VERSION 5.8 ;
BUSBITCHARS "[]" ;
DIVIDERCHAR "/" ;
UNITS
    DATABASE MICRONS 1000 ;
END UNITS

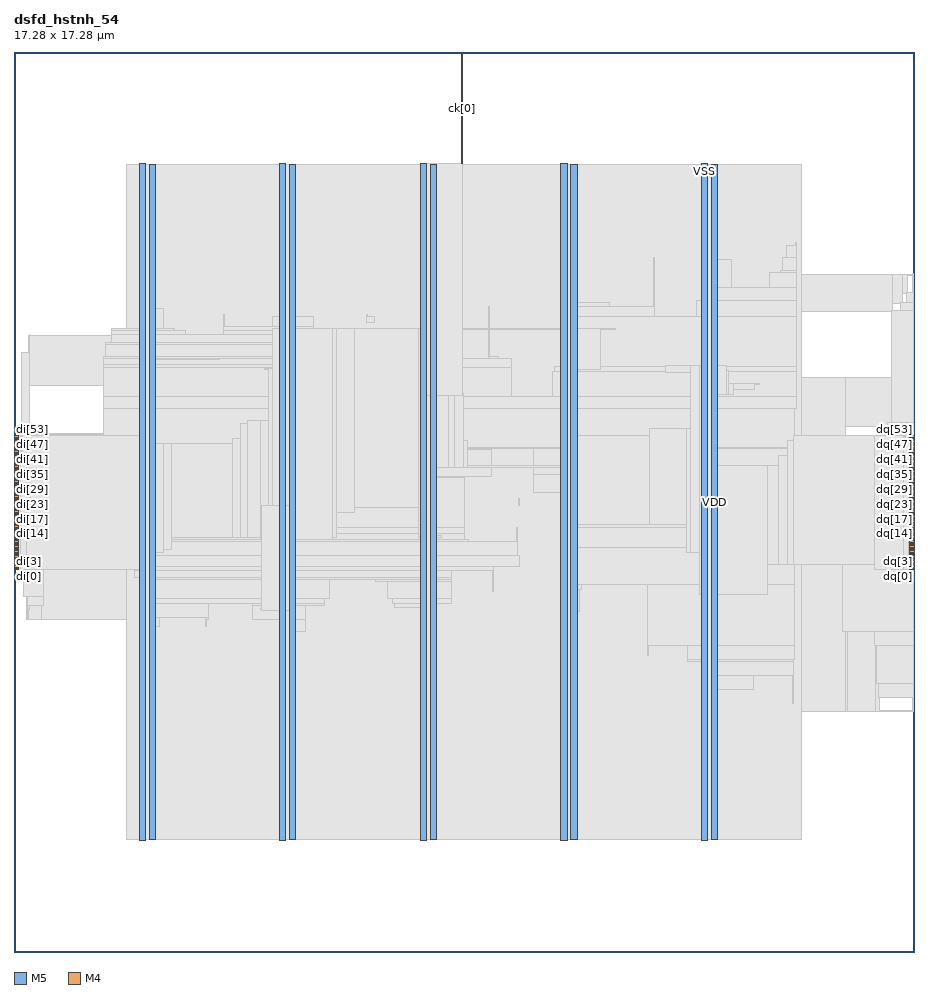
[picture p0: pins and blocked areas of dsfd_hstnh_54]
MACRO dsfd_hstnh_54
  FOREIGN dsfd_hstnh_54 0 0 ;
  CLASS BLOCK ;
  SIZE 17.28 BY 17.28 ;
  PIN ck[0]
    DIRECTION INPUT ;
    USE SIGNAL ;
    PORT
      LAYER M5 ;
        RECT  8.592 17.196 8.616 17.28 ;
    END
    PORT
      LAYER M5 ;
        RECT  8.592 15.143 8.616 17.232 ;
    END
  END ck[0]
  PIN di[0]
    DIRECTION INPUT ;
    USE SIGNAL ;
    PORT
      LAYER M4 ;
        RECT  0 7.344 0.084 7.368 ;
    END
  END di[0]
  PIN di[10]
    DIRECTION INPUT ;
    USE SIGNAL ;
    PORT
      LAYER M4 ;
        RECT  0 7.824 0.084 7.848 ;
    END
  END di[10]
  PIN di[11]
    DIRECTION INPUT ;
    USE SIGNAL ;
    PORT
      LAYER M4 ;
        RECT  0 7.872 0.084 7.896 ;
    END
  END di[11]
  PIN di[12]
    DIRECTION INPUT ;
    USE SIGNAL ;
    PORT
      LAYER M4 ;
        RECT  0 7.92 0.084 7.944 ;
    END
  END di[12]
  PIN di[13]
    DIRECTION INPUT ;
    USE SIGNAL ;
    PORT
      LAYER M4 ;
        RECT  0 7.968 0.084 7.992 ;
    END
  END di[13]
  PIN di[14]
    DIRECTION INPUT ;
    USE SIGNAL ;
    PORT
      LAYER M4 ;
        RECT  0 8.016 0.084 8.04 ;
    END
  END di[14]
  PIN di[15]
    DIRECTION INPUT ;
    USE SIGNAL ;
    PORT
      LAYER M4 ;
        RECT  0 8.064 0.084 8.088 ;
    END
  END di[15]
  PIN di[16]
    DIRECTION INPUT ;
    USE SIGNAL ;
    PORT
      LAYER M4 ;
        RECT  0 8.112 0.084 8.136 ;
    END
  END di[16]
  PIN di[17]
    DIRECTION INPUT ;
    USE SIGNAL ;
    PORT
      LAYER M4 ;
        RECT  0 8.16 0.084 8.184 ;
    END
  END di[17]
  PIN di[18]
    DIRECTION INPUT ;
    USE SIGNAL ;
    PORT
      LAYER M4 ;
        RECT  0 8.208 0.084 8.232 ;
    END
  END di[18]
  PIN di[19]
    DIRECTION INPUT ;
    USE SIGNAL ;
    PORT
      LAYER M4 ;
        RECT  0 8.256 0.084 8.28 ;
    END
  END di[19]
  PIN di[1]
    DIRECTION INPUT ;
    USE SIGNAL ;
    PORT
      LAYER M4 ;
        RECT  0 7.392 0.084 7.416 ;
    END
  END di[1]
  PIN di[20]
    DIRECTION INPUT ;
    USE SIGNAL ;
    PORT
      LAYER M4 ;
        RECT  0 8.304 0.084 8.328 ;
    END
  END di[20]
  PIN di[21]
    DIRECTION INPUT ;
    USE SIGNAL ;
    PORT
      LAYER M4 ;
        RECT  0 8.352 0.084 8.376 ;
    END
  END di[21]
  PIN di[22]
    DIRECTION INPUT ;
    USE SIGNAL ;
    PORT
      LAYER M4 ;
        RECT  0 8.4 0.084 8.424 ;
    END
  END di[22]
  PIN di[23]
    DIRECTION INPUT ;
    USE SIGNAL ;
    PORT
      LAYER M4 ;
        RECT  0 8.448 0.084 8.472 ;
    END
  END di[23]
  PIN di[24]
    DIRECTION INPUT ;
    USE SIGNAL ;
    PORT
      LAYER M4 ;
        RECT  0 8.496 0.084 8.52 ;
    END
  END di[24]
  PIN di[25]
    DIRECTION INPUT ;
    USE SIGNAL ;
    PORT
      LAYER M4 ;
        RECT  0 8.544 0.084 8.568 ;
    END
  END di[25]
  PIN di[26]
    DIRECTION INPUT ;
    USE SIGNAL ;
    PORT
      LAYER M4 ;
        RECT  0 8.592 0.084 8.616 ;
    END
  END di[26]
  PIN di[27]
    DIRECTION INPUT ;
    USE SIGNAL ;
    PORT
      LAYER M4 ;
        RECT  0 8.64 0.084 8.664 ;
    END
  END di[27]
  PIN di[28]
    DIRECTION INPUT ;
    USE SIGNAL ;
    PORT
      LAYER M4 ;
        RECT  0 8.688 0.084 8.712 ;
    END
  END di[28]
  PIN di[29]
    DIRECTION INPUT ;
    USE SIGNAL ;
    PORT
      LAYER M4 ;
        RECT  0 8.736 0.084 8.76 ;
    END
  END di[29]
  PIN di[2]
    DIRECTION INPUT ;
    USE SIGNAL ;
    PORT
      LAYER M4 ;
        RECT  0 7.44 0.084 7.464 ;
    END
  END di[2]
  PIN di[30]
    DIRECTION INPUT ;
    USE SIGNAL ;
    PORT
      LAYER M4 ;
        RECT  0 8.784 0.084 8.808 ;
    END
  END di[30]
  PIN di[31]
    DIRECTION INPUT ;
    USE SIGNAL ;
    PORT
      LAYER M4 ;
        RECT  0 8.832 0.084 8.856 ;
    END
  END di[31]
  PIN di[32]
    DIRECTION INPUT ;
    USE SIGNAL ;
    PORT
      LAYER M4 ;
        RECT  0 8.88 0.084 8.904 ;
    END
  END di[32]
  PIN di[33]
    DIRECTION INPUT ;
    USE SIGNAL ;
    PORT
      LAYER M4 ;
        RECT  0 8.928 0.084 8.952 ;
    END
  END di[33]
  PIN di[34]
    DIRECTION INPUT ;
    USE SIGNAL ;
    PORT
      LAYER M4 ;
        RECT  0 8.976 0.084 9 ;
    END
  END di[34]
  PIN di[35]
    DIRECTION INPUT ;
    USE SIGNAL ;
    PORT
      LAYER M4 ;
        RECT  0 9.024 0.084 9.048 ;
    END
  END di[35]
  PIN di[36]
    DIRECTION INPUT ;
    USE SIGNAL ;
    PORT
      LAYER M4 ;
        RECT  0 9.072 0.084 9.096 ;
    END
  END di[36]
  PIN di[37]
    DIRECTION INPUT ;
    USE SIGNAL ;
    PORT
      LAYER M4 ;
        RECT  0 9.12 0.084 9.144 ;
    END
  END di[37]
  PIN di[38]
    DIRECTION INPUT ;
    USE SIGNAL ;
    PORT
      LAYER M4 ;
        RECT  0 9.168 0.084 9.192 ;
    END
  END di[38]
  PIN di[39]
    DIRECTION INPUT ;
    USE SIGNAL ;
    PORT
      LAYER M4 ;
        RECT  0 9.216 0.084 9.24 ;
    END
  END di[39]
  PIN di[3]
    DIRECTION INPUT ;
    USE SIGNAL ;
    PORT
      LAYER M4 ;
        RECT  0 7.488 0.084 7.512 ;
    END
  END di[3]
  PIN di[40]
    DIRECTION INPUT ;
    USE SIGNAL ;
    PORT
      LAYER M4 ;
        RECT  0 9.264 0.084 9.288 ;
    END
  END di[40]
  PIN di[41]
    DIRECTION INPUT ;
    USE SIGNAL ;
    PORT
      LAYER M4 ;
        RECT  0 9.312 0.084 9.336 ;
    END
  END di[41]
  PIN di[42]
    DIRECTION INPUT ;
    USE SIGNAL ;
    PORT
      LAYER M4 ;
        RECT  0 9.36 0.084 9.384 ;
    END
  END di[42]
  PIN di[43]
    DIRECTION INPUT ;
    USE SIGNAL ;
    PORT
      LAYER M4 ;
        RECT  0 9.408 0.084 9.432 ;
    END
  END di[43]
  PIN di[44]
    DIRECTION INPUT ;
    USE SIGNAL ;
    PORT
      LAYER M4 ;
        RECT  0 9.456 0.084 9.48 ;
    END
  END di[44]
  PIN di[45]
    DIRECTION INPUT ;
    USE SIGNAL ;
    PORT
      LAYER M4 ;
        RECT  0 9.504 0.084 9.528 ;
    END
  END di[45]
  PIN di[46]
    DIRECTION INPUT ;
    USE SIGNAL ;
    PORT
      LAYER M4 ;
        RECT  0 9.552 0.084 9.576 ;
    END
  END di[46]
  PIN di[47]
    DIRECTION INPUT ;
    USE SIGNAL ;
    PORT
      LAYER M4 ;
        RECT  0 9.6 0.084 9.624 ;
    END
  END di[47]
  PIN di[48]
    DIRECTION INPUT ;
    USE SIGNAL ;
    PORT
      LAYER M4 ;
        RECT  0 9.648 0.084 9.672 ;
    END
  END di[48]
  PIN di[49]
    DIRECTION INPUT ;
    USE SIGNAL ;
    PORT
      LAYER M4 ;
        RECT  0 9.696 0.084 9.72 ;
    END
  END di[49]
  PIN di[4]
    DIRECTION INPUT ;
    USE SIGNAL ;
    PORT
      LAYER M4 ;
        RECT  0 7.536 0.084 7.56 ;
    END
  END di[4]
  PIN di[50]
    DIRECTION INPUT ;
    USE SIGNAL ;
    PORT
      LAYER M4 ;
        RECT  0 9.744 0.084 9.768 ;
    END
  END di[50]
  PIN di[51]
    DIRECTION INPUT ;
    USE SIGNAL ;
    PORT
      LAYER M4 ;
        RECT  0 9.792 0.084 9.816 ;
    END
  END di[51]
  PIN di[52]
    DIRECTION INPUT ;
    USE SIGNAL ;
    PORT
      LAYER M4 ;
        RECT  0 9.84 0.084 9.864 ;
    END
  END di[52]
  PIN di[53]
    DIRECTION INPUT ;
    USE SIGNAL ;
    PORT
      LAYER M4 ;
        RECT  0 9.888 0.084 9.912 ;
    END
  END di[53]
  PIN di[5]
    DIRECTION INPUT ;
    USE SIGNAL ;
    PORT
      LAYER M4 ;
        RECT  0 7.584 0.084 7.608 ;
    END
  END di[5]
  PIN di[6]
    DIRECTION INPUT ;
    USE SIGNAL ;
    PORT
      LAYER M4 ;
        RECT  0 7.632 0.084 7.656 ;
    END
  END di[6]
  PIN di[7]
    DIRECTION INPUT ;
    USE SIGNAL ;
    PORT
      LAYER M4 ;
        RECT  0 7.68 0.084 7.704 ;
    END
  END di[7]
  PIN di[8]
    DIRECTION INPUT ;
    USE SIGNAL ;
    PORT
      LAYER M4 ;
        RECT  0 7.728 0.084 7.752 ;
    END
  END di[8]
  PIN di[9]
    DIRECTION INPUT ;
    USE SIGNAL ;
    PORT
      LAYER M4 ;
        RECT  0 7.776 0.084 7.8 ;
    END
  END di[9]
  PIN dq[0]
    DIRECTION OUTPUT ;
    USE SIGNAL ;
    PORT
      LAYER M4 ;
        RECT  17.196 7.344 17.28 7.368 ;
    END
  END dq[0]
  PIN dq[10]
    DIRECTION OUTPUT ;
    USE SIGNAL ;
    PORT
      LAYER M4 ;
        RECT  17.196 7.824 17.28 7.848 ;
    END
  END dq[10]
  PIN dq[11]
    DIRECTION OUTPUT ;
    USE SIGNAL ;
    PORT
      LAYER M4 ;
        RECT  17.196 7.872 17.28 7.896 ;
    END
  END dq[11]
  PIN dq[12]
    DIRECTION OUTPUT ;
    USE SIGNAL ;
    PORT
      LAYER M4 ;
        RECT  17.196 7.92 17.28 7.944 ;
    END
  END dq[12]
  PIN dq[13]
    DIRECTION OUTPUT ;
    USE SIGNAL ;
    PORT
      LAYER M4 ;
        RECT  17.196 7.968 17.28 7.992 ;
    END
  END dq[13]
  PIN dq[14]
    DIRECTION OUTPUT ;
    USE SIGNAL ;
    PORT
      LAYER M4 ;
        RECT  17.196 8.016 17.28 8.04 ;
    END
  END dq[14]
  PIN dq[15]
    DIRECTION OUTPUT ;
    USE SIGNAL ;
    PORT
      LAYER M4 ;
        RECT  17.196 8.064 17.28 8.088 ;
    END
  END dq[15]
  PIN dq[16]
    DIRECTION OUTPUT ;
    USE SIGNAL ;
    PORT
      LAYER M4 ;
        RECT  17.196 8.112 17.28 8.136 ;
    END
  END dq[16]
  PIN dq[17]
    DIRECTION OUTPUT ;
    USE SIGNAL ;
    PORT
      LAYER M4 ;
        RECT  17.196 8.16 17.28 8.184 ;
    END
  END dq[17]
  PIN dq[18]
    DIRECTION OUTPUT ;
    USE SIGNAL ;
    PORT
      LAYER M4 ;
        RECT  17.196 8.208 17.28 8.232 ;
    END
  END dq[18]
  PIN dq[19]
    DIRECTION OUTPUT ;
    USE SIGNAL ;
    PORT
      LAYER M4 ;
        RECT  17.196 8.256 17.28 8.28 ;
    END
  END dq[19]
  PIN dq[1]
    DIRECTION OUTPUT ;
    USE SIGNAL ;
    PORT
      LAYER M4 ;
        RECT  17.196 7.392 17.28 7.416 ;
    END
  END dq[1]
  PIN dq[20]
    DIRECTION OUTPUT ;
    USE SIGNAL ;
    PORT
      LAYER M4 ;
        RECT  17.196 8.304 17.28 8.328 ;
    END
  END dq[20]
  PIN dq[21]
    DIRECTION OUTPUT ;
    USE SIGNAL ;
    PORT
      LAYER M4 ;
        RECT  17.196 8.352 17.28 8.376 ;
    END
  END dq[21]
  PIN dq[22]
    DIRECTION OUTPUT ;
    USE SIGNAL ;
    PORT
      LAYER M4 ;
        RECT  17.196 8.4 17.28 8.424 ;
    END
  END dq[22]
  PIN dq[23]
    DIRECTION OUTPUT ;
    USE SIGNAL ;
    PORT
      LAYER M4 ;
        RECT  17.196 8.448 17.28 8.472 ;
    END
  END dq[23]
  PIN dq[24]
    DIRECTION OUTPUT ;
    USE SIGNAL ;
    PORT
      LAYER M4 ;
        RECT  17.196 8.496 17.28 8.52 ;
    END
  END dq[24]
  PIN dq[25]
    DIRECTION OUTPUT ;
    USE SIGNAL ;
    PORT
      LAYER M4 ;
        RECT  17.196 8.544 17.28 8.568 ;
    END
  END dq[25]
  PIN dq[26]
    DIRECTION OUTPUT ;
    USE SIGNAL ;
    PORT
      LAYER M4 ;
        RECT  17.196 8.592 17.28 8.616 ;
    END
  END dq[26]
  PIN dq[27]
    DIRECTION OUTPUT ;
    USE SIGNAL ;
    PORT
      LAYER M4 ;
        RECT  17.196 8.64 17.28 8.664 ;
    END
  END dq[27]
  PIN dq[28]
    DIRECTION OUTPUT ;
    USE SIGNAL ;
    PORT
      LAYER M4 ;
        RECT  17.196 8.688 17.28 8.712 ;
    END
  END dq[28]
  PIN dq[29]
    DIRECTION OUTPUT ;
    USE SIGNAL ;
    PORT
      LAYER M4 ;
        RECT  17.196 8.736 17.28 8.76 ;
    END
  END dq[29]
  PIN dq[2]
    DIRECTION OUTPUT ;
    USE SIGNAL ;
    PORT
      LAYER M4 ;
        RECT  17.196 7.44 17.28 7.464 ;
    END
  END dq[2]
  PIN dq[30]
    DIRECTION OUTPUT ;
    USE SIGNAL ;
    PORT
      LAYER M4 ;
        RECT  17.196 8.784 17.28 8.808 ;
    END
  END dq[30]
  PIN dq[31]
    DIRECTION OUTPUT ;
    USE SIGNAL ;
    PORT
      LAYER M4 ;
        RECT  17.196 8.832 17.28 8.856 ;
    END
  END dq[31]
  PIN dq[32]
    DIRECTION OUTPUT ;
    USE SIGNAL ;
    PORT
      LAYER M4 ;
        RECT  17.196 8.88 17.28 8.904 ;
    END
  END dq[32]
  PIN dq[33]
    DIRECTION OUTPUT ;
    USE SIGNAL ;
    PORT
      LAYER M4 ;
        RECT  17.196 8.928 17.28 8.952 ;
    END
  END dq[33]
  PIN dq[34]
    DIRECTION OUTPUT ;
    USE SIGNAL ;
    PORT
      LAYER M4 ;
        RECT  17.196 8.976 17.28 9 ;
    END
  END dq[34]
  PIN dq[35]
    DIRECTION OUTPUT ;
    USE SIGNAL ;
    PORT
      LAYER M4 ;
        RECT  17.196 9.024 17.28 9.048 ;
    END
  END dq[35]
  PIN dq[36]
    DIRECTION OUTPUT ;
    USE SIGNAL ;
    PORT
      LAYER M4 ;
        RECT  17.196 9.072 17.28 9.096 ;
    END
  END dq[36]
  PIN dq[37]
    DIRECTION OUTPUT ;
    USE SIGNAL ;
    PORT
      LAYER M4 ;
        RECT  17.196 9.12 17.28 9.144 ;
    END
  END dq[37]
  PIN dq[38]
    DIRECTION OUTPUT ;
    USE SIGNAL ;
    PORT
      LAYER M4 ;
        RECT  17.196 9.168 17.28 9.192 ;
    END
  END dq[38]
  PIN dq[39]
    DIRECTION OUTPUT ;
    USE SIGNAL ;
    PORT
      LAYER M4 ;
        RECT  17.196 9.216 17.28 9.24 ;
    END
  END dq[39]
  PIN dq[3]
    DIRECTION OUTPUT ;
    USE SIGNAL ;
    PORT
      LAYER M4 ;
        RECT  17.196 7.488 17.28 7.512 ;
    END
  END dq[3]
  PIN dq[40]
    DIRECTION OUTPUT ;
    USE SIGNAL ;
    PORT
      LAYER M4 ;
        RECT  17.196 9.264 17.28 9.288 ;
    END
  END dq[40]
  PIN dq[41]
    DIRECTION OUTPUT ;
    USE SIGNAL ;
    PORT
      LAYER M4 ;
        RECT  17.196 9.312 17.28 9.336 ;
    END
  END dq[41]
  PIN dq[42]
    DIRECTION OUTPUT ;
    USE SIGNAL ;
    PORT
      LAYER M4 ;
        RECT  17.196 9.36 17.28 9.384 ;
    END
  END dq[42]
  PIN dq[43]
    DIRECTION OUTPUT ;
    USE SIGNAL ;
    PORT
      LAYER M4 ;
        RECT  17.196 9.408 17.28 9.432 ;
    END
  END dq[43]
  PIN dq[44]
    DIRECTION OUTPUT ;
    USE SIGNAL ;
    PORT
      LAYER M4 ;
        RECT  17.196 9.456 17.28 9.48 ;
    END
  END dq[44]
  PIN dq[45]
    DIRECTION OUTPUT ;
    USE SIGNAL ;
    PORT
      LAYER M4 ;
        RECT  17.196 9.504 17.28 9.528 ;
    END
  END dq[45]
  PIN dq[46]
    DIRECTION OUTPUT ;
    USE SIGNAL ;
    PORT
      LAYER M4 ;
        RECT  17.196 9.552 17.28 9.576 ;
    END
  END dq[46]
  PIN dq[47]
    DIRECTION OUTPUT ;
    USE SIGNAL ;
    PORT
      LAYER M4 ;
        RECT  17.196 9.6 17.28 9.624 ;
    END
  END dq[47]
  PIN dq[48]
    DIRECTION OUTPUT ;
    USE SIGNAL ;
    PORT
      LAYER M4 ;
        RECT  17.196 9.648 17.28 9.672 ;
    END
  END dq[48]
  PIN dq[49]
    DIRECTION OUTPUT ;
    USE SIGNAL ;
    PORT
      LAYER M4 ;
        RECT  17.196 9.696 17.28 9.72 ;
    END
  END dq[49]
  PIN dq[4]
    DIRECTION OUTPUT ;
    USE SIGNAL ;
    PORT
      LAYER M4 ;
        RECT  17.196 7.536 17.28 7.56 ;
    END
  END dq[4]
  PIN dq[50]
    DIRECTION OUTPUT ;
    USE SIGNAL ;
    PORT
      LAYER M4 ;
        RECT  17.196 9.744 17.28 9.768 ;
    END
  END dq[50]
  PIN dq[51]
    DIRECTION OUTPUT ;
    USE SIGNAL ;
    PORT
      LAYER M4 ;
        RECT  17.196 9.792 17.28 9.816 ;
    END
  END dq[51]
  PIN dq[52]
    DIRECTION OUTPUT ;
    USE SIGNAL ;
    PORT
      LAYER M4 ;
        RECT  17.196 9.84 17.28 9.864 ;
    END
  END dq[52]
  PIN dq[53]
    DIRECTION OUTPUT ;
    USE SIGNAL ;
    PORT
      LAYER M4 ;
        RECT  17.196 9.888 17.28 9.912 ;
    END
  END dq[53]
  PIN dq[5]
    DIRECTION OUTPUT ;
    USE SIGNAL ;
    PORT
      LAYER M4 ;
        RECT  17.196 7.584 17.28 7.608 ;
    END
  END dq[5]
  PIN dq[6]
    DIRECTION OUTPUT ;
    USE SIGNAL ;
    PORT
      LAYER M4 ;
        RECT  17.196 7.632 17.28 7.656 ;
    END
  END dq[6]
  PIN dq[7]
    DIRECTION OUTPUT ;
    USE SIGNAL ;
    PORT
      LAYER M4 ;
        RECT  17.196 7.68 17.28 7.704 ;
    END
  END dq[7]
  PIN dq[8]
    DIRECTION OUTPUT ;
    USE SIGNAL ;
    PORT
      LAYER M4 ;
        RECT  17.196 7.728 17.28 7.752 ;
    END
  END dq[8]
  PIN dq[9]
    DIRECTION OUTPUT ;
    USE SIGNAL ;
    PORT
      LAYER M4 ;
        RECT  17.196 7.776 17.28 7.8 ;
    END
  END dq[9]
  PIN VDD
    DIRECTION INOUT ;
    USE POWER ;
    PORT
      LAYER M5 ;
        RECT  13.392 2.151 13.512 15.129 ;
        RECT  10.692 2.151 10.812 15.129 ;
        RECT  7.992 2.151 8.112 15.129 ;
        RECT  5.292 2.151 5.412 15.129 ;
        RECT  2.592 2.151 2.712 15.129 ;
    END
  END VDD
  PIN VSS
    DIRECTION INOUT ;
    USE GROUND ;
    PORT
      LAYER M5 ;
        RECT  13.2 2.137 13.32 15.143 ;
        RECT  10.5 2.137 10.62 15.143 ;
        RECT  7.8 2.137 7.92 15.143 ;
        RECT  5.1 2.137 5.22 15.143 ;
        RECT  2.4 2.137 2.52 15.143 ;
    END
  END VSS
  # OT_OBS_CLOSED layer=M5 d_um=1.536 added=0
  OBS
    LAYER RVTN ;
     RECT  2.16 2.16 15.12 2.295 ;
     RECT  2.16 2.565 15.12 2.835 ;
     RECT  2.16 3.105 15.12 3.375 ;
     RECT  2.16 3.645 15.12 3.915 ;
     RECT  2.16 4.185 15.12 4.455 ;
     RECT  2.16 4.725 15.12 4.995 ;
     RECT  2.16 5.265 15.12 5.535 ;
     RECT  2.16 5.805 15.12 6.075 ;
     RECT  2.16 6.345 15.12 6.615 ;
     RECT  2.16 6.885 15.12 7.155 ;
     RECT  2.16 7.425 15.12 7.695 ;
     RECT  2.16 7.965 15.12 8.235 ;
     RECT  2.16 8.505 15.12 8.775 ;
     RECT  2.16 9.045 15.12 9.315 ;
     RECT  2.16 9.585 15.12 9.855 ;
     RECT  2.16 10.125 15.12 10.395 ;
     RECT  2.16 10.665 15.12 10.935 ;
     RECT  2.16 11.205 15.12 11.475 ;
     RECT  2.16 11.745 15.12 12.015 ;
     RECT  2.16 12.285 15.12 12.555 ;
     RECT  2.16 12.825 15.12 13.095 ;
     RECT  2.16 13.365 15.12 13.635 ;
     RECT  2.16 13.905 15.12 14.175 ;
     RECT  2.16 14.445 15.12 14.715 ;
     RECT  2.16 14.985 15.12 15.12 ;
    LAYER RVTP ;
     RECT  2.16 2.295 15.12 2.565 ;
     RECT  2.16 2.835 15.12 3.105 ;
     RECT  2.16 3.375 15.12 3.645 ;
     RECT  2.16 3.915 15.12 4.185 ;
     RECT  2.16 4.455 15.12 4.725 ;
     RECT  2.16 4.995 15.12 5.265 ;
     RECT  2.16 5.535 15.12 5.805 ;
     RECT  2.16 6.075 15.12 6.345 ;
     RECT  2.16 6.615 15.12 6.885 ;
     RECT  2.16 7.155 15.12 7.425 ;
     RECT  2.16 7.695 15.12 7.965 ;
     RECT  2.16 8.235 15.12 8.505 ;
     RECT  2.16 8.775 15.12 9.045 ;
     RECT  2.16 9.315 15.12 9.585 ;
     RECT  2.16 9.855 15.12 10.125 ;
     RECT  2.16 10.395 15.12 10.665 ;
     RECT  2.16 10.935 15.12 11.205 ;
     RECT  2.16 11.475 15.12 11.745 ;
     RECT  2.16 12.015 15.12 12.285 ;
     RECT  2.16 12.555 15.12 12.825 ;
     RECT  2.16 13.095 15.12 13.365 ;
     RECT  2.16 13.635 15.12 13.905 ;
     RECT  2.16 14.175 15.12 14.445 ;
     RECT  2.16 14.715 15.12 14.985 ;
    LAYER M1 ;
     RECT  2.16 2.151 15.12 15.129 ;
    LAYER M2 ;
     RECT  0.139 7.398 0.175 7.956 ;
     RECT  0.139 11.484 0.175 11.502 ;
     RECT  0.103 8.901 0.211 9.504 ;
     RECT  0.175 6.822 0.247 7.956 ;
     RECT  0.175 10.872 0.283 11.502 ;
     RECT  0.211 8.901 0.319 9.954 ;
     RECT  0.319 8.82 0.347 9.954 ;
     RECT  0.347 8.82 0.527 9.144 ;
     RECT  0.247 6.39 0.535 7.956 ;
     RECT  0.283 10.872 1.867 11.844 ;
     RECT  0.347 9.936 2.047 9.954 ;
     RECT  1.867 10.872 2.047 11.97 ;
     RECT  0.535 6.39 2.16 8.226 ;
     RECT  0.527 9.054 2.16 9.144 ;
     RECT  2.047 9.936 2.16 11.97 ;
     RECT  2.16 2.151 15.12 15.129 ;
     RECT  15.12 4.626 15.971 11.034 ;
     RECT  15.971 4.626 16.007 9.144 ;
     RECT  16.007 4.626 16.547 8.532 ;
     RECT  16.547 4.626 16.619 7.524 ;
     RECT  16.619 5.472 16.691 6.984 ;
     RECT  16.691 5.976 16.727 6.984 ;
     RECT  15.12 12.294 16.871 13.014 ;
     RECT  15.971 10.098 16.943 11.034 ;
     RECT  16.871 12.456 17.051 13.014 ;
     RECT  16.943 10.476 17.087 11.034 ;
     RECT  16.727 5.976 17.123 6.876 ;
     RECT  17.087 10.476 17.123 10.494 ;
     RECT  17.051 12.636 17.159 13.014 ;
     RECT  17.123 6.246 17.231 6.876 ;
     RECT  16.619 4.626 17.267 4.644 ;
     RECT  16.547 8.361 17.267 8.379 ;
     RECT  16.987 9.396 17.267 9.414 ;
     RECT  17.159 12.996 17.267 13.014 ;
    LAYER M3 ;
     RECT  2.415 2.143 2.505 2.413 ;
     RECT  5.115 2.143 5.205 2.413 ;
     RECT  7.815 2.143 7.905 2.413 ;
     RECT  10.515 2.143 10.605 2.413 ;
     RECT  13.215 2.143 13.305 2.413 ;
     RECT  17.244 4.621 17.262 4.891 ;
     RECT  13.215 2.413 13.497 5.035 ;
     RECT  16.596 4.891 17.262 5.161 ;
     RECT  13.215 5.035 14.202 5.305 ;
     RECT  14.94 4.765 14.958 5.305 ;
     RECT  13.215 5.305 14.958 5.575 ;
     RECT  12.924 5.575 14.958 5.611 ;
     RECT  12.168 5.701 12.186 5.881 ;
     RECT  12.924 5.611 14.994 5.881 ;
     RECT  16.56 5.161 17.262 5.881 ;
     RECT  5.115 2.413 5.397 6.151 ;
     RECT  16.524 5.881 17.262 6.151 ;
     RECT  2.415 2.413 2.697 6.241 ;
     RECT  3.672 6.241 3.69 6.385 ;
     RECT  5.115 6.151 5.598 6.385 ;
     RECT  2.415 6.241 2.79 6.421 ;
     RECT  3.672 6.385 3.726 6.421 ;
     RECT  10.515 2.413 10.797 6.547 ;
     RECT  0.252 6.385 0.27 6.583 ;
     RECT  7.815 2.413 8.097 6.619 ;
     RECT  0.252 6.583 0.306 6.655 ;
     RECT  4.572 6.385 5.598 6.655 ;
     RECT  2.415 6.421 3.726 6.691 ;
     RECT  4.572 6.655 5.958 6.691 ;
     RECT  7.308 6.619 8.097 6.691 ;
     RECT  2.415 6.691 5.958 6.781 ;
     RECT  7.272 6.691 8.406 6.781 ;
     RECT  0.252 6.655 0.558 6.817 ;
     RECT  10.515 6.547 10.854 6.961 ;
     RECT  10.515 6.961 10.89 7.051 ;
     RECT  12.168 5.881 14.994 7.051 ;
     RECT  7.164 6.781 8.406 7.123 ;
     RECT  2.415 6.781 6.066 7.159 ;
     RECT  6.948 7.123 8.406 7.159 ;
     RECT  2.415 7.159 8.406 7.195 ;
     RECT  2.304 7.195 8.406 7.321 ;
     RECT  9.18 6.925 9.198 7.321 ;
     RECT  0.18 6.817 0.558 7.393 ;
     RECT  2.304 7.321 9.198 7.393 ;
     RECT  0.144 7.393 0.558 7.421 ;
     RECT  2.304 7.393 9.702 7.619 ;
     RECT  10.515 7.051 14.994 7.771 ;
     RECT  15.912 6.151 17.262 7.771 ;
     RECT  2.304 7.619 9.666 7.889 ;
     RECT  2.304 7.889 8.73 7.925 ;
     RECT  2.304 7.925 8.658 8.041 ;
     RECT  0.144 7.421 0.522 8.093 ;
     RECT  2.268 8.041 8.658 8.141 ;
     RECT  10.515 7.771 17.262 8.141 ;
     RECT  9.648 7.889 9.666 8.159 ;
     RECT  0.18 8.093 0.522 8.203 ;
     RECT  15.948 8.141 17.262 8.384 ;
     RECT  15.948 8.384 17.118 8.621 ;
     RECT  9.684 8.581 9.702 8.699 ;
     RECT  10.515 8.141 14.958 8.815 ;
     RECT  0.18 8.203 0.558 8.816 ;
     RECT  0.18 8.816 0.522 8.827 ;
     RECT  16.884 8.621 17.118 8.909 ;
     RECT  0.108 8.827 0.522 9.005 ;
     RECT  0.108 9.005 0.486 9.101 ;
     RECT  2.304 8.141 8.658 9.115 ;
     RECT  2.268 9.115 8.658 9.121 ;
     RECT  9.972 8.815 14.958 9.163 ;
     RECT  15.948 8.621 16.002 9.163 ;
     RECT  9.972 9.163 16.002 9.347 ;
     RECT  0.108 9.101 0.414 9.389 ;
     RECT  16.956 8.909 17.118 9.391 ;
     RECT  15.948 9.347 16.002 9.437 ;
     RECT  0.108 9.389 0.342 9.509 ;
     RECT  0.144 9.509 0.342 9.581 ;
     RECT  2.268 9.121 9.162 9.643 ;
     RECT  16.956 9.391 17.262 9.643 ;
     RECT  2.052 9.643 9.162 9.661 ;
     RECT  9.972 9.347 14.994 9.661 ;
     RECT  2.052 9.661 14.994 9.691 ;
     RECT  16.92 9.643 17.262 9.691 ;
     RECT  16.848 9.691 17.262 9.739 ;
     RECT  15.948 9.437 15.966 9.779 ;
     RECT  16.776 9.739 17.262 10.157 ;
     RECT  1.728 9.691 14.994 10.435 ;
     RECT  1.728 10.435 15.03 10.661 ;
     RECT  10.332 10.661 15.03 11.138 ;
     RECT  1.728 10.661 9.558 11.213 ;
     RECT  10.368 11.138 15.03 11.237 ;
     RECT  1.728 11.213 6.858 11.273 ;
     RECT  1.728 11.273 6.498 11.399 ;
     RECT  7.815 11.213 9.558 11.399 ;
     RECT  1.728 11.399 5.922 11.435 ;
     RECT  9.108 11.399 9.306 11.435 ;
     RECT  0.144 9.581 0.306 11.507 ;
     RECT  1.764 11.435 5.922 11.669 ;
     RECT  7.815 11.399 8.19 11.669 ;
     RECT  1.764 11.669 5.85 11.705 ;
     RECT  0.288 11.507 0.306 11.849 ;
     RECT  1.872 11.705 5.85 11.849 ;
     RECT  1.872 11.849 3.294 11.939 ;
     RECT  4.032 11.849 5.85 11.939 ;
     RECT  1.872 11.939 3.078 11.975 ;
     RECT  4.032 11.939 5.742 12.011 ;
     RECT  4.968 12.011 5.742 12.209 ;
     RECT  6.768 12.091 6.93 12.209 ;
     RECT  10.515 11.237 15.03 12.209 ;
     RECT  4.032 12.011 4.05 12.245 ;
     RECT  6.768 12.209 6.786 12.245 ;
     RECT  16.848 10.157 17.262 12.317 ;
     RECT  2.415 11.975 2.862 12.353 ;
     RECT  9.108 11.435 9.126 12.389 ;
     RECT  10.515 12.209 12.294 12.389 ;
     RECT  10.515 12.389 11.43 12.479 ;
     RECT  17.028 12.317 17.262 12.479 ;
     RECT  13.104 12.209 15.03 12.515 ;
     RECT  17.136 12.479 17.262 12.659 ;
     RECT  13.215 12.515 15.03 12.749 ;
     RECT  17.244 12.659 17.262 13.019 ;
     RECT  14.508 12.749 15.03 13.055 ;
     RECT  14.724 13.055 15.03 13.091 ;
     RECT  13.215 12.749 13.77 13.289 ;
     RECT  12.276 12.389 12.294 13.325 ;
     RECT  14.76 13.091 15.03 13.325 ;
     RECT  14.832 13.325 15.03 13.559 ;
     RECT  15.012 13.559 15.03 13.631 ;
     RECT  2.415 12.353 2.697 14.867 ;
     RECT  5.115 12.209 5.397 14.867 ;
     RECT  7.815 11.669 8.097 14.867 ;
     RECT  10.515 12.479 10.797 14.867 ;
     RECT  13.215 13.289 13.497 14.867 ;
     RECT  2.415 14.867 2.505 15.137 ;
     RECT  5.115 14.867 5.205 15.137 ;
     RECT  7.815 14.867 7.905 15.137 ;
     RECT  10.515 14.867 10.605 15.137 ;
     RECT  13.215 14.867 13.305 15.137 ;
    LAYER M4 ;
     RECT  0.06 7.344 0.133 9.912 ;
     RECT  0.133 7.344 0.245 9.96 ;
     RECT  0.245 7.344 2.408 9.912 ;
     RECT  2.408 2.148 2.512 15.132 ;
     RECT  2.512 2.418 2.704 14.862 ;
     RECT  2.704 7.68 2.873 9.768 ;
     RECT  2.873 7.728 3.017 9.768 ;
     RECT  2.704 11.376 3.953 11.4 ;
     RECT  3.017 7.968 4.201 9.768 ;
     RECT  4.201 7.968 4.345 9.864 ;
     RECT  4.345 7.968 4.489 10.152 ;
     RECT  4.489 7.968 4.741 10.2 ;
     RECT  4.741 7.92 4.885 10.2 ;
     RECT  4.813 11.184 4.885 11.208 ;
     RECT  4.885 7.92 4.957 11.208 ;
     RECT  4.741 6.576 5.108 6.6 ;
     RECT  4.957 7.92 5.108 11.976 ;
     RECT  5.108 2.148 5.212 15.132 ;
     RECT  5.212 2.418 5.404 14.862 ;
     RECT  5.404 7.92 6.113 11.976 ;
     RECT  6.113 7.968 6.185 11.976 ;
     RECT  6.185 8.448 6.545 11.976 ;
     RECT  6.545 8.544 7.765 11.976 ;
     RECT  7.765 7.968 7.808 11.976 ;
     RECT  7.808 2.148 7.912 15.132 ;
     RECT  7.912 2.418 8.104 14.862 ;
     RECT  8.104 7.968 8.201 7.992 ;
     RECT  8.104 9.312 8.345 11.976 ;
     RECT  8.345 9.312 8.453 10.968 ;
     RECT  8.453 9.312 8.627 10.728 ;
     RECT  8.627 9.312 8.705 9.816 ;
     RECT  8.705 9.312 10.508 9.336 ;
     RECT  8.345 11.952 10.508 11.976 ;
     RECT  10.508 2.148 10.612 15.132 ;
     RECT  10.612 2.418 10.804 14.862 ;
     RECT  10.804 11.184 11.261 11.976 ;
     RECT  11.261 11.952 11.549 11.976 ;
     RECT  10.804 8.208 12.193 9.912 ;
     RECT  12.193 8.208 12.913 10.056 ;
     RECT  12.913 7.68 12.985 10.056 ;
     RECT  12.517 11.136 12.985 11.256 ;
     RECT  12.985 7.68 13.165 11.256 ;
     RECT  13.165 6.864 13.208 11.256 ;
     RECT  13.208 2.148 13.312 15.132 ;
     RECT  13.312 2.418 13.504 14.862 ;
     RECT  13.504 10.704 13.673 11.256 ;
     RECT  13.673 10.704 13.709 11.16 ;
     RECT  13.709 10.704 13.817 10.92 ;
     RECT  13.817 10.8 14.213 10.92 ;
     RECT  14.213 10.896 14.321 10.92 ;
     RECT  13.504 6.864 14.465 9.336 ;
     RECT  14.465 7.44 14.677 9.336 ;
     RECT  14.677 7.44 14.857 9.528 ;
     RECT  14.857 7.44 14.965 9.816 ;
     RECT  14.965 7.44 16.513 9.912 ;
     RECT  16.513 7.344 17.077 9.912 ;
     RECT  17.077 7.344 17.165 10.008 ;
     RECT  17.165 7.344 17.244 9.912 ;
    LAYER M5 ;
     RECT  2.4 2.137 2.52 2.151 ;
     RECT  5.1 2.137 5.22 2.151 ;
     RECT  7.8 2.137 7.92 2.151 ;
     RECT  10.5 2.137 10.62 2.151 ;
     RECT  13.2 2.137 13.32 2.151 ;
     RECT  5.1 2.151 5.412 6.565 ;
     RECT  4.752 6.565 5.412 8.579 ;
     RECT  0.288 8.725 0.312 9.491 ;
     RECT  0.144 9.541 0.168 9.971 ;
     RECT  17.088 9.829 17.112 10.019 ;
     RECT  7.8 2.151 8.112 10.693 ;
     RECT  2.4 2.151 2.712 15.129 ;
     RECT  5.1 8.579 5.412 15.129 ;
     RECT  10.5 2.151 10.812 15.129 ;
     RECT  13.2 2.151 13.512 15.129 ;
     RECT  2.4 15.129 2.52 15.143 ;
     RECT  5.1 15.129 5.22 15.143 ;
     RECT  7.8 10.693 8.616 15.143 ;
     RECT  10.5 15.129 10.62 15.143 ;
     RECT  13.2 15.129 13.32 15.143 ;
  END
END dsfd_hstnh_54
END LIBRARY
